VERSION 5.7 ;
  NOWIREEXTENSIONATPIN ON ;
  DIVIDERCHAR "/" ;
  BUSBITCHARS "[]" ;
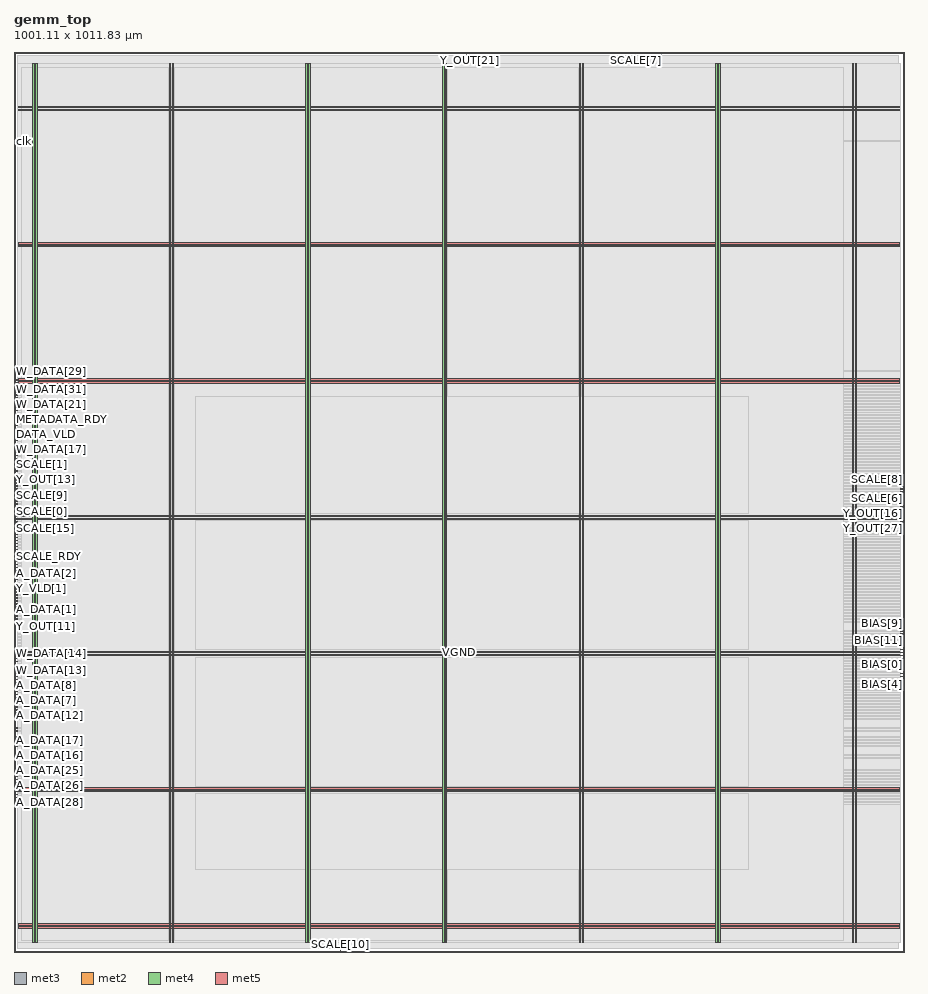
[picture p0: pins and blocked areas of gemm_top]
MACRO gemm_top
  CLASS BLOCK ;
  FOREIGN gemm_top ;
  ORIGIN 0.000 0.000 ;
  SIZE 1001.110 BY 1011.830 ;
  PIN A_DATA[0]
    DIRECTION INPUT ;
    USE SIGNAL ;
    ANTENNAGATEAREA 0.213000 ;
    PORT
      LAYER met3 ;
        RECT 0.000 370.640 4.000 371.240 ;
    END
  END A_DATA[0]
  PIN A_DATA[10]
    DIRECTION INPUT ;
    USE SIGNAL ;
    ANTENNAGATEAREA 0.159000 ;
    PORT
      LAYER met3 ;
        RECT 0.000 292.440 4.000 293.040 ;
    END
  END A_DATA[10]
  PIN A_DATA[11]
    DIRECTION INPUT ;
    USE SIGNAL ;
    ANTENNAGATEAREA 0.159000 ;
    PORT
      LAYER met3 ;
        RECT 0.000 295.840 4.000 296.440 ;
    END
  END A_DATA[11]
  PIN A_DATA[12]
    DIRECTION INPUT ;
    USE SIGNAL ;
    ANTENNAGATEAREA 0.126000 ;
    PORT
      LAYER met3 ;
        RECT 0.000 265.240 4.000 265.840 ;
    END
  END A_DATA[12]
  PIN A_DATA[13]
    DIRECTION INPUT ;
    USE SIGNAL ;
    ANTENNAGATEAREA 0.213000 ;
    PORT
      LAYER met3 ;
        RECT 0.000 285.640 4.000 286.240 ;
    END
  END A_DATA[13]
  PIN A_DATA[14]
    DIRECTION INPUT ;
    USE SIGNAL ;
    ANTENNAGATEAREA 0.213000 ;
    PORT
      LAYER met3 ;
        RECT 0.000 275.440 4.000 276.040 ;
    END
  END A_DATA[14]
  PIN A_DATA[15]
    DIRECTION INPUT ;
    USE SIGNAL ;
    ANTENNAGATEAREA 0.213000 ;
    PORT
      LAYER met3 ;
        RECT 0.000 278.840 4.000 279.440 ;
    END
  END A_DATA[15]
  PIN A_DATA[16]
    DIRECTION INPUT ;
    USE SIGNAL ;
    ANTENNAGATEAREA 0.159000 ;
    PORT
      LAYER met3 ;
        RECT 0.000 221.040 4.000 221.640 ;
    END
  END A_DATA[16]
  PIN A_DATA[17]
    DIRECTION INPUT ;
    USE SIGNAL ;
    ANTENNAGATEAREA 0.159000 ;
    PORT
      LAYER met3 ;
        RECT 0.000 238.040 4.000 238.640 ;
    END
  END A_DATA[17]
  PIN A_DATA[18]
    DIRECTION INPUT ;
    USE SIGNAL ;
    ANTENNAGATEAREA 0.159000 ;
    PORT
      LAYER met3 ;
        RECT 0.000 217.640 4.000 218.240 ;
    END
  END A_DATA[18]
  PIN A_DATA[19]
    DIRECTION INPUT ;
    USE SIGNAL ;
    ANTENNAGATEAREA 0.159000 ;
    PORT
      LAYER met3 ;
        RECT 0.000 234.640 4.000 235.240 ;
    END
  END A_DATA[19]
  PIN A_DATA[1]
    DIRECTION INPUT ;
    USE SIGNAL ;
    ANTENNAGATEAREA 0.213000 ;
    PORT
      LAYER met3 ;
        RECT 0.000 384.240 4.000 384.840 ;
    END
  END A_DATA[1]
  PIN A_DATA[20]
    DIRECTION INPUT ;
    USE SIGNAL ;
    ANTENNAGATEAREA 0.213000 ;
    PORT
      LAYER met3 ;
        RECT 0.000 251.640 4.000 252.240 ;
    END
  END A_DATA[20]
  PIN A_DATA[21]
    DIRECTION INPUT ;
    USE SIGNAL ;
    ANTENNAGATEAREA 0.213000 ;
    PORT
      LAYER met3 ;
        RECT 0.000 231.240 4.000 231.840 ;
    END
  END A_DATA[21]
  PIN A_DATA[22]
    DIRECTION INPUT ;
    USE SIGNAL ;
    ANTENNAGATEAREA 0.213000 ;
    PORT
      LAYER met3 ;
        RECT 0.000 248.240 4.000 248.840 ;
    END
  END A_DATA[22]
  PIN A_DATA[23]
    DIRECTION INPUT ;
    USE SIGNAL ;
    ANTENNAGATEAREA 0.213000 ;
    PORT
      LAYER met3 ;
        RECT 0.000 241.440 4.000 242.040 ;
    END
  END A_DATA[23]
  PIN A_DATA[24]
    DIRECTION INPUT ;
    USE SIGNAL ;
    ANTENNAGATEAREA 0.213000 ;
    PORT
      LAYER met3 ;
        RECT 0.000 200.640 4.000 201.240 ;
    END
  END A_DATA[24]
  PIN A_DATA[25]
    DIRECTION INPUT ;
    USE SIGNAL ;
    ANTENNAGATEAREA 0.213000 ;
    PORT
      LAYER met3 ;
        RECT 0.000 204.040 4.000 204.640 ;
    END
  END A_DATA[25]
  PIN A_DATA[26]
    DIRECTION INPUT ;
    USE SIGNAL ;
    ANTENNAGATEAREA 0.213000 ;
    PORT
      LAYER met3 ;
        RECT 0.000 187.040 4.000 187.640 ;
    END
  END A_DATA[26]
  PIN A_DATA[27]
    DIRECTION INPUT ;
    USE SIGNAL ;
    ANTENNAGATEAREA 0.213000 ;
    PORT
      LAYER met3 ;
        RECT 0.000 183.640 4.000 184.240 ;
    END
  END A_DATA[27]
  PIN A_DATA[28]
    DIRECTION INPUT ;
    USE SIGNAL ;
    ANTENNAGATEAREA 0.213000 ;
    PORT
      LAYER met3 ;
        RECT 0.000 176.840 4.000 177.440 ;
    END
  END A_DATA[28]
  PIN A_DATA[29]
    DIRECTION INPUT ;
    USE SIGNAL ;
    ANTENNAGATEAREA 0.213000 ;
    PORT
      LAYER met3 ;
        RECT 0.000 166.640 4.000 167.240 ;
    END
  END A_DATA[29]
  PIN A_DATA[2]
    DIRECTION INPUT ;
    USE SIGNAL ;
    ANTENNAGATEAREA 0.213000 ;
    PORT
      LAYER met3 ;
        RECT 0.000 425.040 4.000 425.640 ;
    END
  END A_DATA[2]
  PIN A_DATA[30]
    DIRECTION INPUT ;
    USE SIGNAL ;
    ANTENNAGATEAREA 0.159000 ;
    PORT
      LAYER met3 ;
        RECT 0.000 197.240 4.000 197.840 ;
    END
  END A_DATA[30]
  PIN A_DATA[31]
    DIRECTION INPUT ;
    USE SIGNAL ;
    ANTENNAGATEAREA 0.213000 ;
    PORT
      LAYER met3 ;
        RECT 0.000 173.440 4.000 174.040 ;
    END
  END A_DATA[31]
  PIN A_DATA[3]
    DIRECTION INPUT ;
    USE SIGNAL ;
    ANTENNAGATEAREA 0.213000 ;
    PORT
      LAYER met3 ;
        RECT 0.000 414.840 4.000 415.440 ;
    END
  END A_DATA[3]
  PIN A_DATA[4]
    DIRECTION INPUT ;
    USE SIGNAL ;
    ANTENNAGATEAREA 0.159000 ;
    PORT
      LAYER met3 ;
        RECT 0.000 261.840 4.000 262.440 ;
    END
  END A_DATA[4]
  PIN A_DATA[5]
    DIRECTION INPUT ;
    USE SIGNAL ;
    ANTENNAGATEAREA 0.159000 ;
    PORT
      LAYER met3 ;
        RECT 0.000 272.040 4.000 272.640 ;
    END
  END A_DATA[5]
  PIN A_DATA[6]
    DIRECTION INPUT ;
    USE SIGNAL ;
    ANTENNAGATEAREA 0.159000 ;
    PORT
      LAYER met3 ;
        RECT 0.000 268.640 4.000 269.240 ;
    END
  END A_DATA[6]
  PIN A_DATA[7]
    DIRECTION INPUT ;
    USE SIGNAL ;
    ANTENNAGATEAREA 0.159000 ;
    PORT
      LAYER met3 ;
        RECT 0.000 282.240 4.000 282.840 ;
    END
  END A_DATA[7]
  PIN A_DATA[8]
    DIRECTION INPUT ;
    USE SIGNAL ;
    ANTENNAGATEAREA 0.213000 ;
    PORT
      LAYER met3 ;
        RECT 0.000 299.240 4.000 299.840 ;
    END
  END A_DATA[8]
  PIN A_DATA[9]
    DIRECTION INPUT ;
    USE SIGNAL ;
    ANTENNAGATEAREA 0.213000 ;
    PORT
      LAYER met3 ;
        RECT 0.000 302.640 4.000 303.240 ;
    END
  END A_DATA[9]
  PIN A_LEN[0]
    DIRECTION INPUT ;
    USE SIGNAL ;
    ANTENNAGATEAREA 0.213000 ;
    PORT
      LAYER met3 ;
        RECT 0.000 391.040 4.000 391.640 ;
    END
  END A_LEN[0]
  PIN A_LEN[1]
    DIRECTION INPUT ;
    USE SIGNAL ;
    ANTENNAGATEAREA 0.159000 ;
    PORT
      LAYER met3 ;
        RECT 0.000 380.840 4.000 381.440 ;
    END
  END A_LEN[1]
  PIN A_LEN[2]
    DIRECTION INPUT ;
    USE SIGNAL ;
    ANTENNAGATEAREA 0.213000 ;
    PORT
      LAYER met3 ;
        RECT 0.000 455.640 4.000 456.240 ;
    END
  END A_LEN[2]
  PIN A_LEN[3]
    DIRECTION INPUT ;
    USE SIGNAL ;
    ANTENNAGATEAREA 0.126000 ;
    PORT
      LAYER met3 ;
        RECT 0.000 438.640 4.000 439.240 ;
    END
  END A_LEN[3]
  PIN BIAS[0]
    DIRECTION INPUT ;
    USE SIGNAL ;
    ANTENNAGATEAREA 0.495000 ;
    PORT
      LAYER met3 ;
        RECT 997.110 323.040 1001.110 323.640 ;
    END
  END BIAS[0]
  PIN BIAS[10]
    DIRECTION INPUT ;
    USE SIGNAL ;
    ANTENNAGATEAREA 0.495000 ;
    PORT
      LAYER met3 ;
        RECT 997.110 326.440 1001.110 327.040 ;
    END
  END BIAS[10]
  PIN BIAS[11]
    DIRECTION INPUT ;
    USE SIGNAL ;
    ANTENNAGATEAREA 0.495000 ;
    PORT
      LAYER met3 ;
        RECT 997.110 350.240 1001.110 350.840 ;
    END
  END BIAS[11]
  PIN BIAS[12]
    DIRECTION INPUT ;
    USE SIGNAL ;
    ANTENNAGATEAREA 0.495000 ;
    PORT
      LAYER met3 ;
        RECT 997.110 343.440 1001.110 344.040 ;
    END
  END BIAS[12]
  PIN BIAS[13]
    DIRECTION INPUT ;
    USE SIGNAL ;
    ANTENNAGATEAREA 0.495000 ;
    PORT
      LAYER met3 ;
        RECT 997.110 336.640 1001.110 337.240 ;
    END
  END BIAS[13]
  PIN BIAS[14]
    DIRECTION INPUT ;
    USE SIGNAL ;
    ANTENNAGATEAREA 0.495000 ;
    PORT
      LAYER met3 ;
        RECT 997.110 340.040 1001.110 340.640 ;
    END
  END BIAS[14]
  PIN BIAS[15]
    DIRECTION INPUT ;
    USE SIGNAL ;
    ANTENNAGATEAREA 0.426000 ;
    PORT
      LAYER met3 ;
        RECT 997.110 346.840 1001.110 347.440 ;
    END
  END BIAS[15]
  PIN BIAS[1]
    DIRECTION INPUT ;
    USE SIGNAL ;
    ANTENNAGATEAREA 0.742500 ;
    PORT
      LAYER met3 ;
        RECT 997.110 316.240 1001.110 316.840 ;
    END
  END BIAS[1]
  PIN BIAS[2]
    DIRECTION INPUT ;
    USE SIGNAL ;
    ANTENNAGATEAREA 0.495000 ;
    PORT
      LAYER met3 ;
        RECT 997.110 319.640 1001.110 320.240 ;
    END
  END BIAS[2]
  PIN BIAS[3]
    DIRECTION INPUT ;
    USE SIGNAL ;
    ANTENNAGATEAREA 0.742500 ;
    PORT
      LAYER met3 ;
        RECT 997.110 329.840 1001.110 330.440 ;
    END
  END BIAS[3]
  PIN BIAS[4]
    DIRECTION INPUT ;
    USE SIGNAL ;
    ANTENNAGATEAREA 0.495000 ;
    PORT
      LAYER met3 ;
        RECT 997.110 309.440 1001.110 310.040 ;
    END
  END BIAS[4]
  PIN BIAS[5]
    DIRECTION INPUT ;
    USE SIGNAL ;
    ANTENNAGATEAREA 0.495000 ;
    PORT
      LAYER met3 ;
        RECT 997.110 312.840 1001.110 313.440 ;
    END
  END BIAS[5]
  PIN BIAS[6]
    DIRECTION INPUT ;
    USE SIGNAL ;
    ANTENNAGATEAREA 0.495000 ;
    PORT
      LAYER met3 ;
        RECT 997.110 333.240 1001.110 333.840 ;
    END
  END BIAS[6]
  PIN BIAS[7]
    DIRECTION INPUT ;
    USE SIGNAL ;
    ANTENNAGATEAREA 0.495000 ;
    PORT
      LAYER met3 ;
        RECT 997.110 353.640 1001.110 354.240 ;
    END
  END BIAS[7]
  PIN BIAS[8]
    DIRECTION INPUT ;
    USE SIGNAL ;
    ANTENNAGATEAREA 0.495000 ;
    PORT
      LAYER met3 ;
        RECT 997.110 357.040 1001.110 357.640 ;
    END
  END BIAS[8]
  PIN BIAS[9]
    DIRECTION INPUT ;
    USE SIGNAL ;
    ANTENNAGATEAREA 0.495000 ;
    PORT
      LAYER met3 ;
        RECT 997.110 360.440 1001.110 361.040 ;
    END
  END BIAS[9]
  PIN BIAS_NEW
    DIRECTION INPUT ;
    USE SIGNAL ;
    ANTENNAGATEAREA 0.196500 ;
    PORT
      LAYER met3 ;
        RECT 0.000 639.240 4.000 639.840 ;
    END
  END BIAS_NEW
  PIN BIAS_RDY
    DIRECTION OUTPUT ;
    USE SIGNAL ;
    ANTENNADIFFAREA 0.445500 ;
    PORT
      LAYER met3 ;
        RECT 0.000 601.840 4.000 602.440 ;
    END
  END BIAS_RDY
  PIN BIAS_VLD
    DIRECTION INPUT ;
    USE SIGNAL ;
    ANTENNAGATEAREA 0.213000 ;
    PORT
      LAYER met3 ;
        RECT 0.000 588.240 4.000 588.840 ;
    END
  END BIAS_VLD
  PIN DATA_RDY
    DIRECTION OUTPUT ;
    USE SIGNAL ;
    ANTENNADIFFAREA 0.445500 ;
    PORT
      LAYER met3 ;
        RECT 0.000 612.040 4.000 612.640 ;
    END
  END DATA_RDY
  PIN DATA_VLD
    DIRECTION INPUT ;
    USE SIGNAL ;
    ANTENNAGATEAREA 0.196500 ;
    PORT
      LAYER met3 ;
        RECT 0.000 581.440 4.000 582.040 ;
    END
  END DATA_VLD
  PIN K_LEN[0]
    DIRECTION INPUT ;
    USE SIGNAL ;
    ANTENNAGATEAREA 0.213000 ;
    PORT
      LAYER met3 ;
        RECT 0.000 584.840 4.000 585.440 ;
    END
  END K_LEN[0]
  PIN K_LEN[1]
    DIRECTION INPUT ;
    USE SIGNAL ;
    ANTENNAGATEAREA 0.196500 ;
    PORT
      LAYER met3 ;
        RECT 0.000 567.840 4.000 568.440 ;
    END
  END K_LEN[1]
  PIN K_LEN[2]
    DIRECTION INPUT ;
    USE SIGNAL ;
    ANTENNAGATEAREA 0.196500 ;
    PORT
      LAYER met3 ;
        RECT 0.000 571.240 4.000 571.840 ;
    END
  END K_LEN[2]
  PIN K_LEN[3]
    DIRECTION INPUT ;
    USE SIGNAL ;
    ANTENNAGATEAREA 0.196500 ;
    PORT
      LAYER met3 ;
        RECT 0.000 557.640 4.000 558.240 ;
    END
  END K_LEN[3]
  PIN METADATA_RDY
    DIRECTION OUTPUT ;
    USE SIGNAL ;
    ANTENNADIFFAREA 0.445500 ;
    PORT
      LAYER met3 ;
        RECT 0.000 598.440 4.000 599.040 ;
    END
  END METADATA_RDY
  PIN METADATA_VLD
    DIRECTION INPUT ;
    USE SIGNAL ;
    ANTENNAGATEAREA 0.196500 ;
    PORT
      LAYER met3 ;
        RECT 0.000 520.240 4.000 520.840 ;
    END
  END METADATA_VLD
  PIN RELU_EN
    DIRECTION INPUT ;
    USE SIGNAL ;
    ANTENNAGATEAREA 0.126000 ;
    PORT
      LAYER met3 ;
        RECT 0.000 496.440 4.000 497.040 ;
    END
  END RELU_EN
  PIN SCALE[0]
    DIRECTION INPUT ;
    USE SIGNAL ;
    ANTENNAGATEAREA 0.126000 ;
    PORT
      LAYER met3 ;
        RECT 0.000 503.240 4.000 503.840 ;
    END
  END SCALE[0]
  PIN SCALE[10]
    DIRECTION INPUT ;
    USE SIGNAL ;
    ANTENNAGATEAREA 0.126000 ;
    PORT
      LAYER met2 ;
        RECT 367.170 0.000 367.450 4.000 ;
    END
  END SCALE[10]
  PIN SCALE[11]
    DIRECTION INPUT ;
    USE SIGNAL ;
    ANTENNAGATEAREA 0.126000 ;
    PORT
      LAYER met3 ;
        RECT 0.000 489.640 4.000 490.240 ;
    END
  END SCALE[11]
  PIN SCALE[12]
    DIRECTION INPUT ;
    USE SIGNAL ;
    ANTENNAGATEAREA 0.126000 ;
    PORT
      LAYER met3 ;
        RECT 0.000 506.640 4.000 507.240 ;
    END
  END SCALE[12]
  PIN SCALE[13]
    DIRECTION INPUT ;
    USE SIGNAL ;
    ANTENNAGATEAREA 0.126000 ;
    PORT
      LAYER met3 ;
        RECT 0.000 510.040 4.000 510.640 ;
    END
  END SCALE[13]
  PIN SCALE[14]
    DIRECTION INPUT ;
    USE SIGNAL ;
    ANTENNAGATEAREA 0.126000 ;
    PORT
      LAYER met3 ;
        RECT 0.000 554.240 4.000 554.840 ;
    END
  END SCALE[14]
  PIN SCALE[15]
    DIRECTION INPUT ;
    USE SIGNAL ;
    ANTENNAGATEAREA 0.126000 ;
    PORT
      LAYER met3 ;
        RECT 0.000 476.040 4.000 476.640 ;
    END
  END SCALE[15]
  PIN SCALE[1]
    DIRECTION INPUT ;
    USE SIGNAL ;
    ANTENNAGATEAREA 0.126000 ;
    PORT
      LAYER met3 ;
        RECT 0.000 547.440 4.000 548.040 ;
    END
  END SCALE[1]
  PIN SCALE[2]
    DIRECTION INPUT ;
    USE SIGNAL ;
    ANTENNAGATEAREA 0.126000 ;
    PORT
      LAYER met3 ;
        RECT 997.110 506.640 1001.110 507.240 ;
    END
  END SCALE[2]
  PIN SCALE[3]
    DIRECTION INPUT ;
    USE SIGNAL ;
    ANTENNAGATEAREA 0.126000 ;
    PORT
      LAYER met3 ;
        RECT 997.110 527.040 1001.110 527.640 ;
    END
  END SCALE[3]
  PIN SCALE[4]
    DIRECTION INPUT ;
    USE SIGNAL ;
    ANTENNAGATEAREA 0.126000 ;
    PORT
      LAYER met3 ;
        RECT 997.110 523.640 1001.110 524.240 ;
    END
  END SCALE[4]
  PIN SCALE[5]
    DIRECTION INPUT ;
    USE SIGNAL ;
    ANTENNAGATEAREA 0.126000 ;
    PORT
      LAYER met3 ;
        RECT 997.110 520.240 1001.110 520.840 ;
    END
  END SCALE[5]
  PIN SCALE[6]
    DIRECTION INPUT ;
    USE SIGNAL ;
    ANTENNAGATEAREA 0.126000 ;
    PORT
      LAYER met3 ;
        RECT 997.110 510.040 1001.110 510.640 ;
    END
  END SCALE[6]
  PIN SCALE[7]
    DIRECTION INPUT ;
    USE SIGNAL ;
    ANTENNAGATEAREA 0.213000 ;
    PORT
      LAYER met2 ;
        RECT 698.830 1007.830 699.110 1011.830 ;
    END
  END SCALE[7]
  PIN SCALE[8]
    DIRECTION INPUT ;
    USE SIGNAL ;
    ANTENNAGATEAREA 0.196500 ;
    PORT
      LAYER met3 ;
        RECT 997.110 530.440 1001.110 531.040 ;
    END
  END SCALE[8]
  PIN SCALE[9]
    DIRECTION INPUT ;
    USE SIGNAL ;
    ANTENNAGATEAREA 0.126000 ;
    PORT
      LAYER met3 ;
        RECT 0.000 513.440 4.000 514.040 ;
    END
  END SCALE[9]
  PIN SCALE_RDY
    DIRECTION OUTPUT ;
    USE SIGNAL ;
    ANTENNADIFFAREA 0.445500 ;
    PORT
      LAYER met3 ;
        RECT 0.000 435.240 4.000 435.840 ;
    END
  END SCALE_RDY
  PIN SCALE_VLD
    DIRECTION INPUT ;
    USE SIGNAL ;
    ANTENNAGATEAREA 0.196500 ;
    PORT
      LAYER met3 ;
        RECT 0.000 418.240 4.000 418.840 ;
    END
  END SCALE_VLD
  PIN TILE_DONE
    DIRECTION OUTPUT ;
    USE SIGNAL ;
    ANTENNADIFFAREA 0.445500 ;
    PORT
      LAYER met3 ;
        RECT 0.000 625.640 4.000 626.240 ;
    END
  END TILE_DONE
  PIN TILE_LAST
    DIRECTION INPUT ;
    USE SIGNAL ;
    ANTENNAGATEAREA 0.126000 ;
    PORT
      LAYER met3 ;
        RECT 0.000 527.040 4.000 527.640 ;
    END
  END TILE_LAST
  PIN TILE_START
    DIRECTION INPUT ;
    USE SIGNAL ;
    ANTENNAGATEAREA 0.196500 ;
    PORT
      LAYER met3 ;
        RECT 0.000 516.840 4.000 517.440 ;
    END
  END TILE_START
  PIN VGND
    DIRECTION INOUT ;
    USE GROUND ;
    PORT
      LAYER met4 ;
        RECT 24.340 10.640 25.940 998.480 ;
    END
    PORT
      LAYER met4 ;
        RECT 177.940 10.640 179.540 998.480 ;
    END
    PORT
      LAYER met4 ;
        RECT 331.540 10.640 333.140 998.480 ;
    END
    PORT
      LAYER met4 ;
        RECT 485.140 10.640 486.740 998.480 ;
    END
    PORT
      LAYER met4 ;
        RECT 638.740 10.640 640.340 998.480 ;
    END
    PORT
      LAYER met4 ;
        RECT 792.340 10.640 793.940 998.480 ;
    END
    PORT
      LAYER met4 ;
        RECT 945.940 10.640 947.540 998.480 ;
    END
    PORT
      LAYER met5 ;
        RECT 5.280 30.030 995.680 31.630 ;
    END
    PORT
      LAYER met5 ;
        RECT 5.280 183.210 995.680 184.810 ;
    END
    PORT
      LAYER met5 ;
        RECT 5.280 336.390 995.680 337.990 ;
    END
    PORT
      LAYER met5 ;
        RECT 5.280 489.570 995.680 491.170 ;
    END
    PORT
      LAYER met5 ;
        RECT 5.280 642.750 995.680 644.350 ;
    END
    PORT
      LAYER met5 ;
        RECT 5.280 795.930 995.680 797.530 ;
    END
    PORT
      LAYER met5 ;
        RECT 5.280 949.110 995.680 950.710 ;
    END
  END VGND
  PIN VPWR
    DIRECTION INOUT ;
    USE POWER ;
    PORT
      LAYER met4 ;
        RECT 21.040 10.640 22.640 998.480 ;
    END
    PORT
      LAYER met4 ;
        RECT 174.640 10.640 176.240 998.480 ;
    END
    PORT
      LAYER met4 ;
        RECT 328.240 10.640 329.840 998.480 ;
    END
    PORT
      LAYER met4 ;
        RECT 481.840 10.640 483.440 998.480 ;
    END
    PORT
      LAYER met4 ;
        RECT 635.440 10.640 637.040 998.480 ;
    END
    PORT
      LAYER met4 ;
        RECT 789.040 10.640 790.640 998.480 ;
    END
    PORT
      LAYER met4 ;
        RECT 942.640 10.640 944.240 998.480 ;
    END
    PORT
      LAYER met5 ;
        RECT 5.280 26.730 995.680 28.330 ;
    END
    PORT
      LAYER met5 ;
        RECT 5.280 179.910 995.680 181.510 ;
    END
    PORT
      LAYER met5 ;
        RECT 5.280 333.090 995.680 334.690 ;
    END
    PORT
      LAYER met5 ;
        RECT 5.280 486.270 995.680 487.870 ;
    END
    PORT
      LAYER met5 ;
        RECT 5.280 639.450 995.680 641.050 ;
    END
    PORT
      LAYER met5 ;
        RECT 5.280 792.630 995.680 794.230 ;
    END
    PORT
      LAYER met5 ;
        RECT 5.280 945.810 995.680 947.410 ;
    END
  END VPWR
  PIN W_DATA[0]
    DIRECTION INPUT ;
    USE SIGNAL ;
    ANTENNAGATEAREA 0.213000 ;
    PORT
      LAYER met3 ;
        RECT 0.000 312.840 4.000 313.440 ;
    END
  END W_DATA[0]
  PIN W_DATA[10]
    DIRECTION INPUT ;
    USE SIGNAL ;
    ANTENNAGATEAREA 0.213000 ;
    PORT
      LAYER met3 ;
        RECT 0.000 193.840 4.000 194.440 ;
    END
  END W_DATA[10]
  PIN W_DATA[11]
    DIRECTION INPUT ;
    USE SIGNAL ;
    ANTENNAGATEAREA 0.159000 ;
    PORT
      LAYER met3 ;
        RECT 0.000 190.440 4.000 191.040 ;
    END
  END W_DATA[11]
  PIN W_DATA[12]
    DIRECTION INPUT ;
    USE SIGNAL ;
    ANTENNAGATEAREA 0.159000 ;
    PORT
      LAYER met3 ;
        RECT 0.000 306.040 4.000 306.640 ;
    END
  END W_DATA[12]
  PIN W_DATA[13]
    DIRECTION INPUT ;
    USE SIGNAL ;
    ANTENNAGATEAREA 0.159000 ;
    PORT
      LAYER met3 ;
        RECT 0.000 316.240 4.000 316.840 ;
    END
  END W_DATA[13]
  PIN W_DATA[14]
    DIRECTION INPUT ;
    USE SIGNAL ;
    ANTENNAGATEAREA 0.213000 ;
    PORT
      LAYER met3 ;
        RECT 0.000 326.440 4.000 327.040 ;
    END
  END W_DATA[14]
  PIN W_DATA[15]
    DIRECTION INPUT ;
    USE SIGNAL ;
    ANTENNAGATEAREA 0.159000 ;
    PORT
      LAYER met3 ;
        RECT 0.000 329.840 4.000 330.440 ;
    END
  END W_DATA[15]
  PIN W_DATA[16]
    DIRECTION INPUT ;
    USE SIGNAL ;
    ANTENNAGATEAREA 0.213000 ;
    PORT
      LAYER met3 ;
        RECT 0.000 578.040 4.000 578.640 ;
    END
  END W_DATA[16]
  PIN W_DATA[17]
    DIRECTION INPUT ;
    USE SIGNAL ;
    ANTENNAGATEAREA 0.213000 ;
    PORT
      LAYER met3 ;
        RECT 0.000 564.440 4.000 565.040 ;
    END
  END W_DATA[17]
  PIN W_DATA[18]
    DIRECTION INPUT ;
    USE SIGNAL ;
    ANTENNAGATEAREA 0.213000 ;
    PORT
      LAYER met3 ;
        RECT 0.000 561.040 4.000 561.640 ;
    END
  END W_DATA[18]
  PIN W_DATA[19]
    DIRECTION INPUT ;
    USE SIGNAL ;
    ANTENNAGATEAREA 0.213000 ;
    PORT
      LAYER met3 ;
        RECT 0.000 574.640 4.000 575.240 ;
    END
  END W_DATA[19]
  PIN W_DATA[1]
    DIRECTION INPUT ;
    USE SIGNAL ;
    ANTENNAGATEAREA 0.213000 ;
    PORT
      LAYER met3 ;
        RECT 0.000 323.040 4.000 323.640 ;
    END
  END W_DATA[1]
  PIN W_DATA[20]
    DIRECTION INPUT ;
    USE SIGNAL ;
    ANTENNAGATEAREA 0.213000 ;
    PORT
      LAYER met3 ;
        RECT 0.000 618.840 4.000 619.440 ;
    END
  END W_DATA[20]
  PIN W_DATA[21]
    DIRECTION INPUT ;
    USE SIGNAL ;
    ANTENNAGATEAREA 0.213000 ;
    PORT
      LAYER met3 ;
        RECT 0.000 615.440 4.000 616.040 ;
    END
  END W_DATA[21]
  PIN W_DATA[22]
    DIRECTION INPUT ;
    USE SIGNAL ;
    ANTENNAGATEAREA 0.159000 ;
    PORT
      LAYER met3 ;
        RECT 0.000 635.840 4.000 636.440 ;
    END
  END W_DATA[22]
  PIN W_DATA[23]
    DIRECTION INPUT ;
    USE SIGNAL ;
    ANTENNAGATEAREA 0.159000 ;
    PORT
      LAYER met3 ;
        RECT 0.000 629.040 4.000 629.640 ;
    END
  END W_DATA[23]
  PIN W_DATA[24]
    DIRECTION INPUT ;
    USE SIGNAL ;
    ANTENNAGATEAREA 0.213000 ;
    PORT
      LAYER met3 ;
        RECT 0.000 595.040 4.000 595.640 ;
    END
  END W_DATA[24]
  PIN W_DATA[25]
    DIRECTION INPUT ;
    USE SIGNAL ;
    ANTENNAGATEAREA 0.213000 ;
    PORT
      LAYER met3 ;
        RECT 0.000 608.640 4.000 609.240 ;
    END
  END W_DATA[25]
  PIN W_DATA[26]
    DIRECTION INPUT ;
    USE SIGNAL ;
    ANTENNAGATEAREA 0.213000 ;
    PORT
      LAYER met3 ;
        RECT 0.000 591.640 4.000 592.240 ;
    END
  END W_DATA[26]
  PIN W_DATA[27]
    DIRECTION INPUT ;
    USE SIGNAL ;
    ANTENNAGATEAREA 0.213000 ;
    PORT
      LAYER met3 ;
        RECT 0.000 605.240 4.000 605.840 ;
    END
  END W_DATA[27]
  PIN W_DATA[28]
    DIRECTION INPUT ;
    USE SIGNAL ;
    ANTENNAGATEAREA 0.213000 ;
    PORT
      LAYER met3 ;
        RECT 0.000 622.240 4.000 622.840 ;
    END
  END W_DATA[28]
  PIN W_DATA[29]
    DIRECTION INPUT ;
    USE SIGNAL ;
    ANTENNAGATEAREA 0.213000 ;
    PORT
      LAYER met3 ;
        RECT 0.000 652.840 4.000 653.440 ;
    END
  END W_DATA[29]
  PIN W_DATA[2]
    DIRECTION INPUT ;
    USE SIGNAL ;
    ANTENNAGATEAREA 0.213000 ;
    PORT
      LAYER met3 ;
        RECT 0.000 309.440 4.000 310.040 ;
    END
  END W_DATA[2]
  PIN W_DATA[30]
    DIRECTION INPUT ;
    USE SIGNAL ;
    ANTENNAGATEAREA 0.213000 ;
    PORT
      LAYER met3 ;
        RECT 0.000 642.640 4.000 643.240 ;
    END
  END W_DATA[30]
  PIN W_DATA[31]
    DIRECTION INPUT ;
    USE SIGNAL ;
    ANTENNAGATEAREA 0.213000 ;
    PORT
      LAYER met3 ;
        RECT 0.000 632.440 4.000 633.040 ;
    END
  END W_DATA[31]
  PIN W_DATA[3]
    DIRECTION INPUT ;
    USE SIGNAL ;
    ANTENNAGATEAREA 0.213000 ;
    PORT
      LAYER met3 ;
        RECT 0.000 319.640 4.000 320.240 ;
    END
  END W_DATA[3]
  PIN W_DATA[4]
    DIRECTION INPUT ;
    USE SIGNAL ;
    ANTENNAGATEAREA 0.213000 ;
    PORT
      LAYER met3 ;
        RECT 0.000 445.440 4.000 446.040 ;
    END
  END W_DATA[4]
  PIN W_DATA[5]
    DIRECTION INPUT ;
    USE SIGNAL ;
    ANTENNAGATEAREA 0.213000 ;
    PORT
      LAYER met3 ;
        RECT 0.000 377.440 4.000 378.040 ;
    END
  END W_DATA[5]
  PIN W_DATA[6]
    DIRECTION INPUT ;
    USE SIGNAL ;
    ANTENNAGATEAREA 0.213000 ;
    PORT
      LAYER met3 ;
        RECT 0.000 452.240 4.000 452.840 ;
    END
  END W_DATA[6]
  PIN W_DATA[7]
    DIRECTION INPUT ;
    USE SIGNAL ;
    ANTENNAGATEAREA 0.213000 ;
    PORT
      LAYER met3 ;
        RECT 0.000 448.840 4.000 449.440 ;
    END
  END W_DATA[7]
  PIN W_DATA[8]
    DIRECTION INPUT ;
    USE SIGNAL ;
    ANTENNAGATEAREA 0.213000 ;
    PORT
      LAYER met3 ;
        RECT 0.000 180.240 4.000 180.840 ;
    END
  END W_DATA[8]
  PIN W_DATA[9]
    DIRECTION INPUT ;
    USE SIGNAL ;
    ANTENNAGATEAREA 0.159000 ;
    PORT
      LAYER met3 ;
        RECT 0.000 170.040 4.000 170.640 ;
    END
  END W_DATA[9]
  PIN W_LEN[0]
    DIRECTION INPUT ;
    USE SIGNAL ;
    ANTENNAGATEAREA 0.196500 ;
    PORT
      LAYER met3 ;
        RECT 0.000 482.840 4.000 483.440 ;
    END
  END W_LEN[0]
  PIN W_LEN[1]
    DIRECTION INPUT ;
    USE SIGNAL ;
    ANTENNAGATEAREA 0.159000 ;
    PORT
      LAYER met3 ;
        RECT 0.000 411.440 4.000 412.040 ;
    END
  END W_LEN[1]
  PIN W_LEN[2]
    DIRECTION INPUT ;
    USE SIGNAL ;
    ANTENNAGATEAREA 0.213000 ;
    PORT
      LAYER met3 ;
        RECT 0.000 479.440 4.000 480.040 ;
    END
  END W_LEN[2]
  PIN W_LEN[3]
    DIRECTION INPUT ;
    USE SIGNAL ;
    ANTENNAGATEAREA 0.213000 ;
    PORT
      LAYER met3 ;
        RECT 0.000 493.040 4.000 493.640 ;
    END
  END W_LEN[3]
  PIN Y_OUT[0]
    DIRECTION OUTPUT ;
    USE SIGNAL ;
    ANTENNADIFFAREA 0.445500 ;
    PORT
      LAYER met3 ;
        RECT 0.000 465.840 4.000 466.440 ;
    END
  END Y_OUT[0]
  PIN Y_OUT[10]
    DIRECTION OUTPUT ;
    USE SIGNAL ;
    ANTENNADIFFAREA 0.445500 ;
    PORT
      LAYER met3 ;
        RECT 0.000 550.840 4.000 551.440 ;
    END
  END Y_OUT[10]
  PIN Y_OUT[11]
    DIRECTION OUTPUT ;
    USE SIGNAL ;
    ANTENNADIFFAREA 0.445500 ;
    PORT
      LAYER met3 ;
        RECT 0.000 374.040 4.000 374.640 ;
    END
  END Y_OUT[11]
  PIN Y_OUT[12]
    DIRECTION OUTPUT ;
    USE SIGNAL ;
    ANTENNADIFFAREA 0.445500 ;
    PORT
      LAYER met3 ;
        RECT 0.000 537.240 4.000 537.840 ;
    END
  END Y_OUT[12]
  PIN Y_OUT[13]
    DIRECTION OUTPUT ;
    USE SIGNAL ;
    ANTENNADIFFAREA 0.445500 ;
    PORT
      LAYER met3 ;
        RECT 0.000 530.440 4.000 531.040 ;
    END
  END Y_OUT[13]
  PIN Y_OUT[14]
    DIRECTION OUTPUT ;
    USE SIGNAL ;
    ANTENNADIFFAREA 0.445500 ;
    PORT
      LAYER met3 ;
        RECT 0.000 533.840 4.000 534.440 ;
    END
  END Y_OUT[14]
  PIN Y_OUT[15]
    DIRECTION OUTPUT ;
    USE SIGNAL ;
    ANTENNADIFFAREA 0.445500 ;
    PORT
      LAYER met3 ;
        RECT 0.000 523.640 4.000 524.240 ;
    END
  END Y_OUT[15]
  PIN Y_OUT[16]
    DIRECTION OUTPUT ;
    USE SIGNAL ;
    ANTENNADIFFAREA 0.445500 ;
    PORT
      LAYER met3 ;
        RECT 997.110 493.040 1001.110 493.640 ;
    END
  END Y_OUT[16]
  PIN Y_OUT[17]
    DIRECTION OUTPUT ;
    USE SIGNAL ;
    ANTENNADIFFAREA 0.445500 ;
    PORT
      LAYER met3 ;
        RECT 997.110 499.840 1001.110 500.440 ;
    END
  END Y_OUT[17]
  PIN Y_OUT[18]
    DIRECTION OUTPUT ;
    USE SIGNAL ;
    ANTENNADIFFAREA 0.445500 ;
    PORT
      LAYER met3 ;
        RECT 997.110 496.440 1001.110 497.040 ;
    END
  END Y_OUT[18]
  PIN Y_OUT[19]
    DIRECTION OUTPUT ;
    USE SIGNAL ;
    ANTENNADIFFAREA 0.445500 ;
    PORT
      LAYER met3 ;
        RECT 997.110 489.640 1001.110 490.240 ;
    END
  END Y_OUT[19]
  PIN Y_OUT[1]
    DIRECTION OUTPUT ;
    USE SIGNAL ;
    ANTENNADIFFAREA 0.445500 ;
    PORT
      LAYER met3 ;
        RECT 0.000 469.240 4.000 469.840 ;
    END
  END Y_OUT[1]
  PIN Y_OUT[20]
    DIRECTION OUTPUT ;
    USE SIGNAL ;
    ANTENNADIFFAREA 0.445500 ;
    PORT
      LAYER met2 ;
        RECT 515.290 1007.830 515.570 1011.830 ;
    END
  END Y_OUT[20]
  PIN Y_OUT[21]
    DIRECTION OUTPUT ;
    USE SIGNAL ;
    ANTENNADIFFAREA 0.445500 ;
    PORT
      LAYER met2 ;
        RECT 512.070 1007.830 512.350 1011.830 ;
    END
  END Y_OUT[21]
  PIN Y_OUT[22]
    DIRECTION OUTPUT ;
    USE SIGNAL ;
    ANTENNADIFFAREA 0.445500 ;
    PORT
      LAYER met2 ;
        RECT 508.850 1007.830 509.130 1011.830 ;
    END
  END Y_OUT[22]
  PIN Y_OUT[23]
    DIRECTION OUTPUT ;
    USE SIGNAL ;
    ANTENNADIFFAREA 0.445500 ;
    PORT
      LAYER met2 ;
        RECT 518.510 1007.830 518.790 1011.830 ;
    END
  END Y_OUT[23]
  PIN Y_OUT[24]
    DIRECTION OUTPUT ;
    USE SIGNAL ;
    ANTENNADIFFAREA 0.445500 ;
    PORT
      LAYER met3 ;
        RECT 997.110 479.440 1001.110 480.040 ;
    END
  END Y_OUT[24]
  PIN Y_OUT[25]
    DIRECTION OUTPUT ;
    USE SIGNAL ;
    ANTENNADIFFAREA 0.445500 ;
    PORT
      LAYER met3 ;
        RECT 997.110 482.840 1001.110 483.440 ;
    END
  END Y_OUT[25]
  PIN Y_OUT[26]
    DIRECTION OUTPUT ;
    USE SIGNAL ;
    ANTENNADIFFAREA 0.445500 ;
    PORT
      LAYER met3 ;
        RECT 997.110 486.240 1001.110 486.840 ;
    END
  END Y_OUT[26]
  PIN Y_OUT[27]
    DIRECTION OUTPUT ;
    USE SIGNAL ;
    ANTENNADIFFAREA 0.445500 ;
    PORT
      LAYER met3 ;
        RECT 997.110 476.040 1001.110 476.640 ;
    END
  END Y_OUT[27]
  PIN Y_OUT[28]
    DIRECTION OUTPUT ;
    USE SIGNAL ;
    ANTENNADIFFAREA 0.445500 ;
    PORT
      LAYER met2 ;
        RECT 724.590 1007.830 724.870 1011.830 ;
    END
  END Y_OUT[28]
  PIN Y_OUT[29]
    DIRECTION OUTPUT ;
    USE SIGNAL ;
    ANTENNADIFFAREA 0.445500 ;
    PORT
      LAYER met2 ;
        RECT 727.810 1007.830 728.090 1011.830 ;
    END
  END Y_OUT[29]
  PIN Y_OUT[2]
    DIRECTION OUTPUT ;
    USE SIGNAL ;
    ANTENNADIFFAREA 0.445500 ;
    PORT
      LAYER met3 ;
        RECT 0.000 459.040 4.000 459.640 ;
    END
  END Y_OUT[2]
  PIN Y_OUT[30]
    DIRECTION OUTPUT ;
    USE SIGNAL ;
    ANTENNADIFFAREA 0.445500 ;
    PORT
      LAYER met2 ;
        RECT 721.370 1007.830 721.650 1011.830 ;
    END
  END Y_OUT[30]
  PIN Y_OUT[31]
    DIRECTION OUTPUT ;
    USE SIGNAL ;
    ANTENNADIFFAREA 0.445500 ;
    PORT
      LAYER met3 ;
        RECT 997.110 516.840 1001.110 517.440 ;
    END
  END Y_OUT[31]
  PIN Y_OUT[3]
    DIRECTION OUTPUT ;
    USE SIGNAL ;
    ANTENNADIFFAREA 0.445500 ;
    PORT
      LAYER met3 ;
        RECT 0.000 462.440 4.000 463.040 ;
    END
  END Y_OUT[3]
  PIN Y_OUT[4]
    DIRECTION OUTPUT ;
    USE SIGNAL ;
    ANTENNADIFFAREA 0.445500 ;
    PORT
      LAYER met3 ;
        RECT 0.000 486.240 4.000 486.840 ;
    END
  END Y_OUT[4]
  PIN Y_OUT[5]
    DIRECTION OUTPUT ;
    USE SIGNAL ;
    ANTENNADIFFAREA 0.445500 ;
    PORT
      LAYER met3 ;
        RECT 0.000 421.640 4.000 422.240 ;
    END
  END Y_OUT[5]
  PIN Y_OUT[6]
    DIRECTION OUTPUT ;
    USE SIGNAL ;
    ANTENNADIFFAREA 0.445500 ;
    PORT
      LAYER met3 ;
        RECT 0.000 428.440 4.000 429.040 ;
    END
  END Y_OUT[6]
  PIN Y_OUT[7]
    DIRECTION OUTPUT ;
    USE SIGNAL ;
    ANTENNADIFFAREA 0.445500 ;
    PORT
      LAYER met3 ;
        RECT 0.000 472.640 4.000 473.240 ;
    END
  END Y_OUT[7]
  PIN Y_OUT[8]
    DIRECTION OUTPUT ;
    USE SIGNAL ;
    ANTENNADIFFAREA 0.445500 ;
    PORT
      LAYER met3 ;
        RECT 0.000 540.640 4.000 541.240 ;
    END
  END Y_OUT[8]
  PIN Y_OUT[9]
    DIRECTION OUTPUT ;
    USE SIGNAL ;
    ANTENNADIFFAREA 0.445500 ;
    PORT
      LAYER met3 ;
        RECT 0.000 544.040 4.000 544.640 ;
    END
  END Y_OUT[9]
  PIN Y_RDY
    DIRECTION INPUT ;
    USE SIGNAL ;
    ANTENNAGATEAREA 0.196500 ;
    PORT
      LAYER met3 ;
        RECT 0.000 499.840 4.000 500.440 ;
    END
  END Y_RDY
  PIN Y_VLD[0]
    DIRECTION OUTPUT ;
    USE SIGNAL ;
    ANTENNADIFFAREA 0.445500 ;
    PORT
      LAYER met3 ;
        RECT 0.000 397.840 4.000 398.440 ;
    END
  END Y_VLD[0]
  PIN Y_VLD[1]
    DIRECTION OUTPUT ;
    USE SIGNAL ;
    ANTENNADIFFAREA 0.445500 ;
    PORT
      LAYER met3 ;
        RECT 0.000 408.040 4.000 408.640 ;
    END
  END Y_VLD[1]
  PIN Y_VLD[2]
    DIRECTION OUTPUT ;
    USE SIGNAL ;
    ANTENNADIFFAREA 0.445500 ;
    PORT
      LAYER met3 ;
        RECT 0.000 387.640 4.000 388.240 ;
    END
  END Y_VLD[2]
  PIN Y_VLD[3]
    DIRECTION OUTPUT ;
    USE SIGNAL ;
    ANTENNADIFFAREA 0.445500 ;
    PORT
      LAYER met3 ;
        RECT 0.000 401.240 4.000 401.840 ;
    END
  END Y_VLD[3]
  PIN Y_VLD[4]
    DIRECTION OUTPUT ;
    USE SIGNAL ;
    ANTENNADIFFAREA 0.445500 ;
    PORT
      LAYER met3 ;
        RECT 0.000 442.040 4.000 442.640 ;
    END
  END Y_VLD[4]
  PIN Y_VLD[5]
    DIRECTION OUTPUT ;
    USE SIGNAL ;
    ANTENNADIFFAREA 0.445500 ;
    PORT
      LAYER met3 ;
        RECT 0.000 404.640 4.000 405.240 ;
    END
  END Y_VLD[5]
  PIN Y_VLD[6]
    DIRECTION OUTPUT ;
    USE SIGNAL ;
    ANTENNADIFFAREA 0.445500 ;
    PORT
      LAYER met3 ;
        RECT 0.000 431.840 4.000 432.440 ;
    END
  END Y_VLD[6]
  PIN Y_VLD[7]
    DIRECTION OUTPUT ;
    USE SIGNAL ;
    ANTENNADIFFAREA 0.445500 ;
    PORT
      LAYER met3 ;
        RECT 0.000 394.440 4.000 395.040 ;
    END
  END Y_VLD[7]
  PIN clk
    DIRECTION INPUT ;
    USE SIGNAL ;
    ANTENNAGATEAREA 1.286700 ;
    ANTENNADIFFAREA 0.434700 ;
    PORT
      LAYER met3 ;
        RECT 0.000 911.240 4.000 911.840 ;
    END
  END clk
  PIN rst_n
    DIRECTION INPUT ;
    USE SIGNAL ;
    ANTENNAGATEAREA 0.126000 ;
    PORT
      LAYER met3 ;
        RECT 0.000 289.040 4.000 289.640 ;
    END
  END rst_n
  OBS
      LAYER nwell ;
        RECT 5.330 10.795 995.630 998.430 ;
      LAYER li1 ;
        RECT 5.520 10.795 995.440 998.325 ;
      LAYER met1 ;
        RECT 4.210 10.640 995.440 998.480 ;
      LAYER met2 ;
        RECT 4.230 1007.550 508.570 1007.830 ;
        RECT 509.410 1007.550 511.790 1007.830 ;
        RECT 512.630 1007.550 515.010 1007.830 ;
        RECT 515.850 1007.550 518.230 1007.830 ;
        RECT 519.070 1007.550 698.550 1007.830 ;
        RECT 699.390 1007.550 721.090 1007.830 ;
        RECT 721.930 1007.550 724.310 1007.830 ;
        RECT 725.150 1007.550 727.530 1007.830 ;
        RECT 728.370 1007.550 994.430 1007.830 ;
        RECT 4.230 4.280 994.430 1007.550 ;
        RECT 4.230 4.000 366.890 4.280 ;
        RECT 367.730 4.000 994.430 4.280 ;
      LAYER met3 ;
        RECT 3.990 912.240 997.110 998.405 ;
        RECT 4.400 910.840 997.110 912.240 ;
        RECT 3.990 653.840 997.110 910.840 ;
        RECT 4.400 652.440 997.110 653.840 ;
        RECT 3.990 643.640 997.110 652.440 ;
        RECT 4.400 642.240 997.110 643.640 ;
        RECT 3.990 640.240 997.110 642.240 ;
        RECT 4.400 638.840 997.110 640.240 ;
        RECT 3.990 636.840 997.110 638.840 ;
        RECT 4.400 635.440 997.110 636.840 ;
        RECT 3.990 633.440 997.110 635.440 ;
        RECT 4.400 632.040 997.110 633.440 ;
        RECT 3.990 630.040 997.110 632.040 ;
        RECT 4.400 628.640 997.110 630.040 ;
        RECT 3.990 626.640 997.110 628.640 ;
        RECT 4.400 625.240 997.110 626.640 ;
        RECT 3.990 623.240 997.110 625.240 ;
        RECT 4.400 621.840 997.110 623.240 ;
        RECT 3.990 619.840 997.110 621.840 ;
        RECT 4.400 618.440 997.110 619.840 ;
        RECT 3.990 616.440 997.110 618.440 ;
        RECT 4.400 615.040 997.110 616.440 ;
        RECT 3.990 613.040 997.110 615.040 ;
        RECT 4.400 611.640 997.110 613.040 ;
        RECT 3.990 609.640 997.110 611.640 ;
        RECT 4.400 608.240 997.110 609.640 ;
        RECT 3.990 606.240 997.110 608.240 ;
        RECT 4.400 604.840 997.110 606.240 ;
        RECT 3.990 602.840 997.110 604.840 ;
        RECT 4.400 601.440 997.110 602.840 ;
        RECT 3.990 599.440 997.110 601.440 ;
        RECT 4.400 598.040 997.110 599.440 ;
        RECT 3.990 596.040 997.110 598.040 ;
        RECT 4.400 594.640 997.110 596.040 ;
        RECT 3.990 592.640 997.110 594.640 ;
        RECT 4.400 591.240 997.110 592.640 ;
        RECT 3.990 589.240 997.110 591.240 ;
        RECT 4.400 587.840 997.110 589.240 ;
        RECT 3.990 585.840 997.110 587.840 ;
        RECT 4.400 584.440 997.110 585.840 ;
        RECT 3.990 582.440 997.110 584.440 ;
        RECT 4.400 581.040 997.110 582.440 ;
        RECT 3.990 579.040 997.110 581.040 ;
        RECT 4.400 577.640 997.110 579.040 ;
        RECT 3.990 575.640 997.110 577.640 ;
        RECT 4.400 574.240 997.110 575.640 ;
        RECT 3.990 572.240 997.110 574.240 ;
        RECT 4.400 570.840 997.110 572.240 ;
        RECT 3.990 568.840 997.110 570.840 ;
        RECT 4.400 567.440 997.110 568.840 ;
        RECT 3.990 565.440 997.110 567.440 ;
        RECT 4.400 564.040 997.110 565.440 ;
        RECT 3.990 562.040 997.110 564.040 ;
        RECT 4.400 560.640 997.110 562.040 ;
        RECT 3.990 558.640 997.110 560.640 ;
        RECT 4.400 557.240 997.110 558.640 ;
        RECT 3.990 555.240 997.110 557.240 ;
        RECT 4.400 553.840 997.110 555.240 ;
        RECT 3.990 551.840 997.110 553.840 ;
        RECT 4.400 550.440 997.110 551.840 ;
        RECT 3.990 548.440 997.110 550.440 ;
        RECT 4.400 547.040 997.110 548.440 ;
        RECT 3.990 545.040 997.110 547.040 ;
        RECT 4.400 543.640 997.110 545.040 ;
        RECT 3.990 541.640 997.110 543.640 ;
        RECT 4.400 540.240 997.110 541.640 ;
        RECT 3.990 538.240 997.110 540.240 ;
        RECT 4.400 536.840 997.110 538.240 ;
        RECT 3.990 534.840 997.110 536.840 ;
        RECT 4.400 533.440 997.110 534.840 ;
        RECT 3.990 531.440 997.110 533.440 ;
        RECT 4.400 530.040 996.710 531.440 ;
        RECT 3.990 528.040 997.110 530.040 ;
        RECT 4.400 526.640 996.710 528.040 ;
        RECT 3.990 524.640 997.110 526.640 ;
        RECT 4.400 523.240 996.710 524.640 ;
        RECT 3.990 521.240 997.110 523.240 ;
        RECT 4.400 519.840 996.710 521.240 ;
        RECT 3.990 517.840 997.110 519.840 ;
        RECT 4.400 516.440 996.710 517.840 ;
        RECT 3.990 514.440 997.110 516.440 ;
        RECT 4.400 513.040 997.110 514.440 ;
        RECT 3.990 511.040 997.110 513.040 ;
        RECT 4.400 509.640 996.710 511.040 ;
        RECT 3.990 507.640 997.110 509.640 ;
        RECT 4.400 506.240 996.710 507.640 ;
        RECT 3.990 504.240 997.110 506.240 ;
        RECT 4.400 502.840 997.110 504.240 ;
        RECT 3.990 500.840 997.110 502.840 ;
        RECT 4.400 499.440 996.710 500.840 ;
        RECT 3.990 497.440 997.110 499.440 ;
        RECT 4.400 496.040 996.710 497.440 ;
        RECT 3.990 494.040 997.110 496.040 ;
        RECT 4.400 492.640 996.710 494.040 ;
        RECT 3.990 490.640 997.110 492.640 ;
        RECT 4.400 489.240 996.710 490.640 ;
        RECT 3.990 487.240 997.110 489.240 ;
        RECT 4.400 485.840 996.710 487.240 ;
        RECT 3.990 483.840 997.110 485.840 ;
        RECT 4.400 482.440 996.710 483.840 ;
        RECT 3.990 480.440 997.110 482.440 ;
        RECT 4.400 479.040 996.710 480.440 ;
        RECT 3.990 477.040 997.110 479.040 ;
        RECT 4.400 475.640 996.710 477.040 ;
        RECT 3.990 473.640 997.110 475.640 ;
        RECT 4.400 472.240 997.110 473.640 ;
        RECT 3.990 470.240 997.110 472.240 ;
        RECT 4.400 468.840 997.110 470.240 ;
        RECT 3.990 466.840 997.110 468.840 ;
        RECT 4.400 465.440 997.110 466.840 ;
        RECT 3.990 463.440 997.110 465.440 ;
        RECT 4.400 462.040 997.110 463.440 ;
        RECT 3.990 460.040 997.110 462.040 ;
        RECT 4.400 458.640 997.110 460.040 ;
        RECT 3.990 456.640 997.110 458.640 ;
        RECT 4.400 455.240 997.110 456.640 ;
        RECT 3.990 453.240 997.110 455.240 ;
        RECT 4.400 451.840 997.110 453.240 ;
        RECT 3.990 449.840 997.110 451.840 ;
        RECT 4.400 448.440 997.110 449.840 ;
        RECT 3.990 446.440 997.110 448.440 ;
        RECT 4.400 445.040 997.110 446.440 ;
        RECT 3.990 443.040 997.110 445.040 ;
        RECT 4.400 441.640 997.110 443.040 ;
        RECT 3.990 439.640 997.110 441.640 ;
        RECT 4.400 438.240 997.110 439.640 ;
        RECT 3.990 436.240 997.110 438.240 ;
        RECT 4.400 434.840 997.110 436.240 ;
        RECT 3.990 432.840 997.110 434.840 ;
        RECT 4.400 431.440 997.110 432.840 ;
        RECT 3.990 429.440 997.110 431.440 ;
        RECT 4.400 428.040 997.110 429.440 ;
        RECT 3.990 426.040 997.110 428.040 ;
        RECT 4.400 424.640 997.110 426.040 ;
        RECT 3.990 422.640 997.110 424.640 ;
        RECT 4.400 421.240 997.110 422.640 ;
        RECT 3.990 419.240 997.110 421.240 ;
        RECT 4.400 417.840 997.110 419.240 ;
        RECT 3.990 415.840 997.110 417.840 ;
        RECT 4.400 414.440 997.110 415.840 ;
        RECT 3.990 412.440 997.110 414.440 ;
        RECT 4.400 411.040 997.110 412.440 ;
        RECT 3.990 409.040 997.110 411.040 ;
        RECT 4.400 407.640 997.110 409.040 ;
        RECT 3.990 405.640 997.110 407.640 ;
        RECT 4.400 404.240 997.110 405.640 ;
        RECT 3.990 402.240 997.110 404.240 ;
        RECT 4.400 400.840 997.110 402.240 ;
        RECT 3.990 398.840 997.110 400.840 ;
        RECT 4.400 397.440 997.110 398.840 ;
        RECT 3.990 395.440 997.110 397.440 ;
        RECT 4.400 394.040 997.110 395.440 ;
        RECT 3.990 392.040 997.110 394.040 ;
        RECT 4.400 390.640 997.110 392.040 ;
        RECT 3.990 388.640 997.110 390.640 ;
        RECT 4.400 387.240 997.110 388.640 ;
        RECT 3.990 385.240 997.110 387.240 ;
        RECT 4.400 383.840 997.110 385.240 ;
        RECT 3.990 381.840 997.110 383.840 ;
        RECT 4.400 380.440 997.110 381.840 ;
        RECT 3.990 378.440 997.110 380.440 ;
        RECT 4.400 377.040 997.110 378.440 ;
        RECT 3.990 375.040 997.110 377.040 ;
        RECT 4.400 373.640 997.110 375.040 ;
        RECT 3.990 371.640 997.110 373.640 ;
        RECT 4.400 370.240 997.110 371.640 ;
        RECT 3.990 361.440 997.110 370.240 ;
        RECT 3.990 360.040 996.710 361.440 ;
        RECT 3.990 358.040 997.110 360.040 ;
        RECT 3.990 356.640 996.710 358.040 ;
        RECT 3.990 354.640 997.110 356.640 ;
        RECT 3.990 353.240 996.710 354.640 ;
        RECT 3.990 351.240 997.110 353.240 ;
        RECT 3.990 349.840 996.710 351.240 ;
        RECT 3.990 347.840 997.110 349.840 ;
        RECT 3.990 346.440 996.710 347.840 ;
        RECT 3.990 344.440 997.110 346.440 ;
        RECT 3.990 343.040 996.710 344.440 ;
        RECT 3.990 341.040 997.110 343.040 ;
        RECT 3.990 339.640 996.710 341.040 ;
        RECT 3.990 337.640 997.110 339.640 ;
        RECT 3.990 336.240 996.710 337.640 ;
        RECT 3.990 334.240 997.110 336.240 ;
        RECT 3.990 332.840 996.710 334.240 ;
        RECT 3.990 330.840 997.110 332.840 ;
        RECT 4.400 329.440 996.710 330.840 ;
        RECT 3.990 327.440 997.110 329.440 ;
        RECT 4.400 326.040 996.710 327.440 ;
        RECT 3.990 324.040 997.110 326.040 ;
        RECT 4.400 322.640 996.710 324.040 ;
        RECT 3.990 320.640 997.110 322.640 ;
        RECT 4.400 319.240 996.710 320.640 ;
        RECT 3.990 317.240 997.110 319.240 ;
        RECT 4.400 315.840 996.710 317.240 ;
        RECT 3.990 313.840 997.110 315.840 ;
        RECT 4.400 312.440 996.710 313.840 ;
        RECT 3.990 310.440 997.110 312.440 ;
        RECT 4.400 309.040 996.710 310.440 ;
        RECT 3.990 307.040 997.110 309.040 ;
        RECT 4.400 305.640 997.110 307.040 ;
        RECT 3.990 303.640 997.110 305.640 ;
        RECT 4.400 302.240 997.110 303.640 ;
        RECT 3.990 300.240 997.110 302.240 ;
        RECT 4.400 298.840 997.110 300.240 ;
        RECT 3.990 296.840 997.110 298.840 ;
        RECT 4.400 295.440 997.110 296.840 ;
        RECT 3.990 293.440 997.110 295.440 ;
        RECT 4.400 292.040 997.110 293.440 ;
        RECT 3.990 290.040 997.110 292.040 ;
        RECT 4.400 288.640 997.110 290.040 ;
        RECT 3.990 286.640 997.110 288.640 ;
        RECT 4.400 285.240 997.110 286.640 ;
        RECT 3.990 283.240 997.110 285.240 ;
        RECT 4.400 281.840 997.110 283.240 ;
        RECT 3.990 279.840 997.110 281.840 ;
        RECT 4.400 278.440 997.110 279.840 ;
        RECT 3.990 276.440 997.110 278.440 ;
        RECT 4.400 275.040 997.110 276.440 ;
        RECT 3.990 273.040 997.110 275.040 ;
        RECT 4.400 271.640 997.110 273.040 ;
        RECT 3.990 269.640 997.110 271.640 ;
        RECT 4.400 268.240 997.110 269.640 ;
        RECT 3.990 266.240 997.110 268.240 ;
        RECT 4.400 264.840 997.110 266.240 ;
        RECT 3.990 262.840 997.110 264.840 ;
        RECT 4.400 261.440 997.110 262.840 ;
        RECT 3.990 252.640 997.110 261.440 ;
        RECT 4.400 251.240 997.110 252.640 ;
        RECT 3.990 249.240 997.110 251.240 ;
        RECT 4.400 247.840 997.110 249.240 ;
        RECT 3.990 242.440 997.110 247.840 ;
        RECT 4.400 241.040 997.110 242.440 ;
        RECT 3.990 239.040 997.110 241.040 ;
        RECT 4.400 237.640 997.110 239.040 ;
        RECT 3.990 235.640 997.110 237.640 ;
        RECT 4.400 234.240 997.110 235.640 ;
        RECT 3.990 232.240 997.110 234.240 ;
        RECT 4.400 230.840 997.110 232.240 ;
        RECT 3.990 222.040 997.110 230.840 ;
        RECT 4.400 220.640 997.110 222.040 ;
        RECT 3.990 218.640 997.110 220.640 ;
        RECT 4.400 217.240 997.110 218.640 ;
        RECT 3.990 205.040 997.110 217.240 ;
        RECT 4.400 203.640 997.110 205.040 ;
        RECT 3.990 201.640 997.110 203.640 ;
        RECT 4.400 200.240 997.110 201.640 ;
        RECT 3.990 198.240 997.110 200.240 ;
        RECT 4.400 196.840 997.110 198.240 ;
        RECT 3.990 194.840 997.110 196.840 ;
        RECT 4.400 193.440 997.110 194.840 ;
        RECT 3.990 191.440 997.110 193.440 ;
        RECT 4.400 190.040 997.110 191.440 ;
        RECT 3.990 188.040 997.110 190.040 ;
        RECT 4.400 186.640 997.110 188.040 ;
        RECT 3.990 184.640 997.110 186.640 ;
        RECT 4.400 183.240 997.110 184.640 ;
        RECT 3.990 181.240 997.110 183.240 ;
        RECT 4.400 179.840 997.110 181.240 ;
        RECT 3.990 177.840 997.110 179.840 ;
        RECT 4.400 176.440 997.110 177.840 ;
        RECT 3.990 174.440 997.110 176.440 ;
        RECT 4.400 173.040 997.110 174.440 ;
        RECT 3.990 171.040 997.110 173.040 ;
        RECT 4.400 169.640 997.110 171.040 ;
        RECT 3.990 167.640 997.110 169.640 ;
        RECT 4.400 166.240 997.110 167.640 ;
        RECT 3.990 10.715 997.110 166.240 ;
      LAYER met4 ;
        RECT 8.575 13.095 20.640 993.985 ;
        RECT 23.040 13.095 23.940 993.985 ;
        RECT 26.340 13.095 174.240 993.985 ;
        RECT 176.640 13.095 177.540 993.985 ;
        RECT 179.940 13.095 327.840 993.985 ;
        RECT 330.240 13.095 331.140 993.985 ;
        RECT 333.540 13.095 481.440 993.985 ;
        RECT 483.840 13.095 484.740 993.985 ;
        RECT 487.140 13.095 635.040 993.985 ;
        RECT 637.440 13.095 638.340 993.985 ;
        RECT 640.740 13.095 788.640 993.985 ;
        RECT 791.040 13.095 791.940 993.985 ;
        RECT 794.340 13.095 932.585 993.985 ;
      LAYER met5 ;
        RECT 203.900 492.770 825.580 624.700 ;
        RECT 203.900 339.590 825.580 484.670 ;
        RECT 203.900 186.410 825.580 331.490 ;
        RECT 203.900 92.700 825.580 178.310 ;
  END
END gemm_top
END LIBRARY

